VERSION 5.7 ;
BUSBITCHARS "[]" ;
DIVIDERCHAR "/" ;

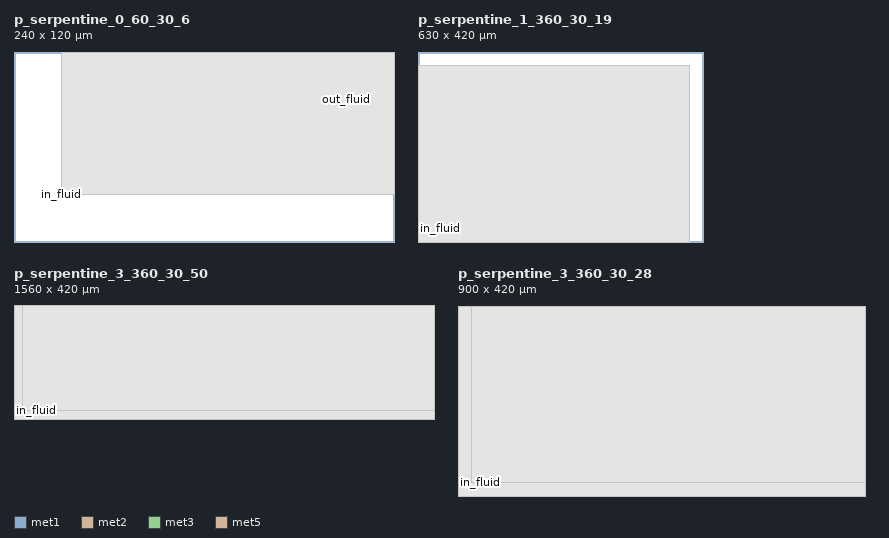
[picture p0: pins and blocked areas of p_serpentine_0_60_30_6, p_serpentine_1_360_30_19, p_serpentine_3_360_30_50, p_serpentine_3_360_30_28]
MACRO p_serpentine_0_60_30_6
  CLASS CORE ;
  ORIGIN  0 0 ;
  FOREIGN p_serpentine_0_60_30_6 0 0 ;
  SIZE 240 BY 120 ;
  SYMMETRY X Y ;
  SITE CoreSite ;
  PIN in_fluid
    DIRECTION INPUT ;
    USE SIGNAL ;
    PORT
      LAYER met1 ;
        RECT 29.5 29.5 30.5 30.5 ;
    END
  END in_fluid
  PIN out_fluid
    DIRECTION OUTPUT ;
    USE SIGNAL ;
    PORT
      LAYER met1 ;
        RECT 209.5 89.5 210.5 90.5 ;
    END
  END out_fluid
  OBS
    LAYER met1 ;
      RECT 30 30 240 120 ;
  END
  PROPERTY CatenaDesignType "deviceLevel" ;
END p_serpentine_0_60_30_6

MACRO p_serpentine_1_360_30_19
  CLASS CORE ;
  ORIGIN  0 0 ;
  FOREIGN p_serpentine_1_360_30_19 0 0 ;
  SIZE 630 BY 420 ;
  SYMMETRY X Y ;
  SITE CoreSite ;
  PIN in_fluid
    DIRECTION INPUT ;
    USE SIGNAL ;
    PORT
      LAYER met2 ;
        RECT 29.5 29.5 30.5 30.5 ;
    END
  END in_fluid
  PIN out_fluid
    DIRECTION OUTPUT ;
    USE SIGNAL ;
    PORT
      LAYER met3 ;
        RECT 29.5 29.5 30.5 30.5 ;
    END
  END out_fluid
  OBS
    LAYER met2 ;
      RECT 30 30 600 390 ;
    LAYER met3 ;
      RECT 0 0 600 390 ;
  END
  PROPERTY CatenaDesignType "deviceLevel" ;
END p_serpentine_1_360_30_19

MACRO p_serpentine_3_360_30_50
  CLASS CORE ;
  ORIGIN  0 0 ;
  FOREIGN p_serpentine_3_360_30_50 0 0 ;
  SIZE 1560 BY 420 ;
  SYMMETRY X Y ;
  SITE CoreSite ;
  PIN in_fluid
    DIRECTION INPUT ;
    USE SIGNAL ;
    PORT
      LAYER met2 ;
        RECT 29.5 29.5 30.5 30.5 ;
    END
  END in_fluid
  PIN out_fluid
    DIRECTION OUTPUT ;
    USE SIGNAL ;
    PORT
      LAYER met5 ;
        RECT 29.5 29.5 30.5 30.5 ;
    END
  END out_fluid
  OBS
    LAYER met2 ;
      RECT 30 30 1560 420 ;
    LAYER met3 ;
      RECT 0 0 1560 420 ;
    LAYER met4 ;
      RECT 0 0 1560 420 ;
    LAYER met5 ;
      RECT 30 30 1560 420 ;
  END
  PROPERTY CatenaDesignType "deviceLevel" ;
END p_serpentine_3_360_30_50

MACRO p_serpentine_3_360_30_28
  CLASS CORE ;
  ORIGIN  0 0 ;
  FOREIGN p_serpentine_3_360_30_28 0 0 ;
  SIZE 900 BY 420 ;
  SYMMETRY X Y ;
  SITE CoreSite ;
  PIN in_fluid
    DIRECTION INPUT ;
    USE SIGNAL ;
    PORT
      LAYER met2 ;
        RECT 29.5 29.5 30.5 30.5 ;
    END
  END in_fluid
  PIN out_fluid
    DIRECTION OUTPUT ;
    USE SIGNAL ;
    PORT
      LAYER met5 ;
        RECT 29.5 29.5 30.5 30.5 ;
    END
  END out_fluid
  OBS
    LAYER met2 ;
      RECT 30 30 900 420 ;
    LAYER met3 ;
      RECT 0 0 900 420 ;
    LAYER met4 ;
      RECT 0 0 900 420 ;
    LAYER met5 ;
      RECT 30 30 900 420 ;
  END
  PROPERTY CatenaDesignType "deviceLevel" ;
END p_serpentine_3_360_30_28

